One B-rep face of a CAD part: STEP entity #60630.
In plain terms, the planar face has unit normal (0, 0, 1).
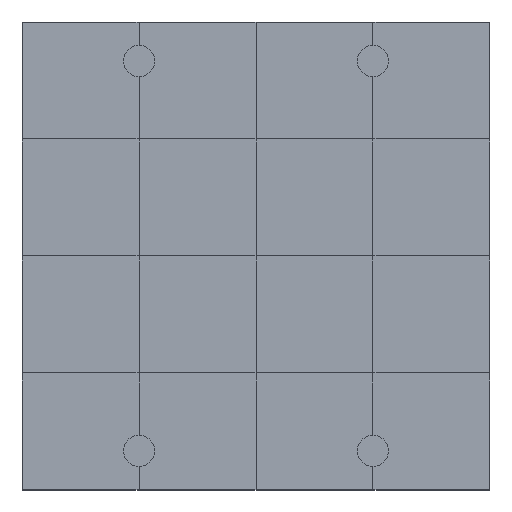
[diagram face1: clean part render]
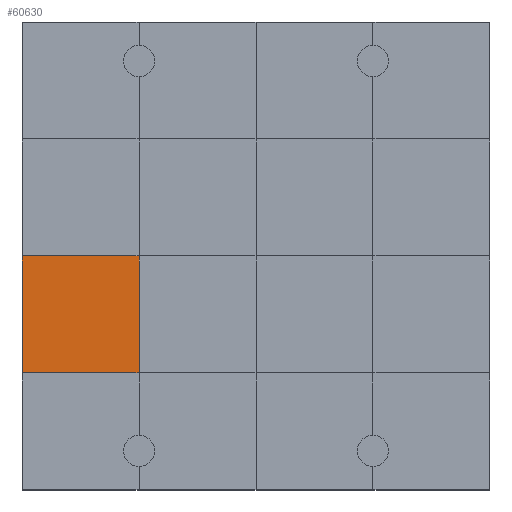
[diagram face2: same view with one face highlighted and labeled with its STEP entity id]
Its self-contained STEP definition (entity closure, numbers rounded to 3 decimals):
#60180 = VERTEX_POINT('',#60181);
#60181 = CARTESIAN_POINT('',(0.,3.,1.2));
#60195 = PLANE('',#60196);
#60196 = AXIS2_PLACEMENT_3D('',#60197,#60198,#60199);
#60197 = CARTESIAN_POINT('',(0.,3.,0.));
#60198 = DIRECTION('',(1.,0.,-0.));
#60199 = DIRECTION('',(0.,0.,1.));
#60221 = PLANE('',#60222);
#60222 = AXIS2_PLACEMENT_3D('',#60223,#60224,#60225);
#60223 = CARTESIAN_POINT('',(0.,0.,1.2));
#60224 = DIRECTION('',(0.,0.,1.));
#60225 = DIRECTION('',(1.,0.,-0.));
#60372 = VERTEX_POINT('',#60373);
#60373 = CARTESIAN_POINT('',(3.,3.,1.2));
#60394 = EDGE_CURVE('',#60180,#60372,#60395,.T.);
#60395 = SURFACE_CURVE('',#60396,(#60400,#60407),.PCURVE_S1.);
#60396 = LINE('',#60397,#60398);
#60397 = CARTESIAN_POINT('',(0.,3.,1.2));
#60398 = VECTOR('',#60399,1.);
#60399 = DIRECTION('',(1.,0.,-0.));
#60400 = PCURVE('',#60221,#60401);
#60401 = DEFINITIONAL_REPRESENTATION('',(#60402),#60406);
#60402 = LINE('',#60403,#60404);
#60403 = CARTESIAN_POINT('',(0.,3.));
#60404 = VECTOR('',#60405,1.);
#60405 = DIRECTION('',(1.,0.));
#60406 = ( GEOMETRIC_REPRESENTATION_CONTEXT(2) 
PARAMETRIC_REPRESENTATION_CONTEXT() REPRESENTATION_CONTEXT('2D SPACE',''
  ) );
#60407 = PCURVE('',#60408,#60413);
#60408 = PLANE('',#60409);
#60409 = AXIS2_PLACEMENT_3D('',#60410,#60411,#60412);
#60410 = CARTESIAN_POINT('',(0.,3.,1.2));
#60411 = DIRECTION('',(0.,0.,1.));
#60412 = DIRECTION('',(1.,0.,-0.));
#60413 = DEFINITIONAL_REPRESENTATION('',(#60414),#60418);
#60414 = LINE('',#60415,#60416);
#60415 = CARTESIAN_POINT('',(0.,0.));
#60416 = VECTOR('',#60417,1.);
#60417 = DIRECTION('',(1.,0.));
#60418 = ( GEOMETRIC_REPRESENTATION_CONTEXT(2) 
PARAMETRIC_REPRESENTATION_CONTEXT() REPRESENTATION_CONTEXT('2D SPACE',''
  ) );
#60453 = VERTEX_POINT('',#60454);
#60454 = CARTESIAN_POINT('',(0.,6.,1.2));
#60480 = EDGE_CURVE('',#60180,#60453,#60481,.T.);
#60481 = SURFACE_CURVE('',#60482,(#60486,#60493),.PCURVE_S1.);
#60482 = LINE('',#60483,#60484);
#60483 = CARTESIAN_POINT('',(0.,3.,1.2));
#60484 = VECTOR('',#60485,1.);
#60485 = DIRECTION('',(-0.,1.,0.));
#60486 = PCURVE('',#60195,#60487);
#60487 = DEFINITIONAL_REPRESENTATION('',(#60488),#60492);
#60488 = LINE('',#60489,#60490);
#60489 = CARTESIAN_POINT('',(1.2,0.));
#60490 = VECTOR('',#60491,1.);
#60491 = DIRECTION('',(0.,-1.));
#60492 = ( GEOMETRIC_REPRESENTATION_CONTEXT(2) 
PARAMETRIC_REPRESENTATION_CONTEXT() REPRESENTATION_CONTEXT('2D SPACE',''
  ) );
#60493 = PCURVE('',#60408,#60494);
#60494 = DEFINITIONAL_REPRESENTATION('',(#60495),#60499);
#60495 = LINE('',#60496,#60497);
#60496 = CARTESIAN_POINT('',(0.,0.));
#60497 = VECTOR('',#60498,1.);
#60498 = DIRECTION('',(0.,1.));
#60499 = ( GEOMETRIC_REPRESENTATION_CONTEXT(2) 
PARAMETRIC_REPRESENTATION_CONTEXT() REPRESENTATION_CONTEXT('2D SPACE',''
  ) );
#60630 = ADVANCED_FACE('',(#60631),#60408,.T.);
#60631 = FACE_BOUND('',#60632,.T.);
#60632 = EDGE_LOOP('',(#60633,#60634,#60635,#60663));
#60633 = ORIENTED_EDGE('',*,*,#60480,.F.);
#60634 = ORIENTED_EDGE('',*,*,#60394,.T.);
#60635 = ORIENTED_EDGE('',*,*,#60636,.T.);
#60636 = EDGE_CURVE('',#60372,#60637,#60639,.T.);
#60637 = VERTEX_POINT('',#60638);
#60638 = CARTESIAN_POINT('',(3.,6.,1.2));
#60639 = SURFACE_CURVE('',#60640,(#60644,#60651),.PCURVE_S1.);
#60640 = LINE('',#60641,#60642);
#60641 = CARTESIAN_POINT('',(3.,3.,1.2));
#60642 = VECTOR('',#60643,1.);
#60643 = DIRECTION('',(-0.,1.,0.));
#60644 = PCURVE('',#60408,#60645);
#60645 = DEFINITIONAL_REPRESENTATION('',(#60646),#60650);
#60646 = LINE('',#60647,#60648);
#60647 = CARTESIAN_POINT('',(3.,0.));
#60648 = VECTOR('',#60649,1.);
#60649 = DIRECTION('',(0.,1.));
#60650 = ( GEOMETRIC_REPRESENTATION_CONTEXT(2) 
PARAMETRIC_REPRESENTATION_CONTEXT() REPRESENTATION_CONTEXT('2D SPACE',''
  ) );
#60651 = PCURVE('',#60652,#60657);
#60652 = PLANE('',#60653);
#60653 = AXIS2_PLACEMENT_3D('',#60654,#60655,#60656);
#60654 = CARTESIAN_POINT('',(3.,3.,1.2));
#60655 = DIRECTION('',(0.,0.,1.));
#60656 = DIRECTION('',(1.,0.,-0.));
#60657 = DEFINITIONAL_REPRESENTATION('',(#60658),#60662);
#60658 = LINE('',#60659,#60660);
#60659 = CARTESIAN_POINT('',(0.,0.));
#60660 = VECTOR('',#60661,1.);
#60661 = DIRECTION('',(0.,1.));
#60662 = ( GEOMETRIC_REPRESENTATION_CONTEXT(2) 
PARAMETRIC_REPRESENTATION_CONTEXT() REPRESENTATION_CONTEXT('2D SPACE',''
  ) );
#60663 = ORIENTED_EDGE('',*,*,#60664,.F.);
#60664 = EDGE_CURVE('',#60453,#60637,#60665,.T.);
#60665 = SURFACE_CURVE('',#60666,(#60670,#60677),.PCURVE_S1.);
#60666 = LINE('',#60667,#60668);
#60667 = CARTESIAN_POINT('',(0.,6.,1.2));
#60668 = VECTOR('',#60669,1.);
#60669 = DIRECTION('',(1.,0.,-0.));
#60670 = PCURVE('',#60408,#60671);
#60671 = DEFINITIONAL_REPRESENTATION('',(#60672),#60676);
#60672 = LINE('',#60673,#60674);
#60673 = CARTESIAN_POINT('',(0.,3.));
#60674 = VECTOR('',#60675,1.);
#60675 = DIRECTION('',(1.,0.));
#60676 = ( GEOMETRIC_REPRESENTATION_CONTEXT(2) 
PARAMETRIC_REPRESENTATION_CONTEXT() REPRESENTATION_CONTEXT('2D SPACE',''
  ) );
#60677 = PCURVE('',#60678,#60683);
#60678 = PLANE('',#60679);
#60679 = AXIS2_PLACEMENT_3D('',#60680,#60681,#60682);
#60680 = CARTESIAN_POINT('',(0.,6.,1.2));
#60681 = DIRECTION('',(0.,0.,1.));
#60682 = DIRECTION('',(1.,0.,-0.));
#60683 = DEFINITIONAL_REPRESENTATION('',(#60684),#60688);
#60684 = LINE('',#60685,#60686);
#60685 = CARTESIAN_POINT('',(0.,0.));
#60686 = VECTOR('',#60687,1.);
#60687 = DIRECTION('',(1.,0.));
#60688 = ( GEOMETRIC_REPRESENTATION_CONTEXT(2) 
PARAMETRIC_REPRESENTATION_CONTEXT() REPRESENTATION_CONTEXT('2D SPACE',''
  ) );
